VERSION 5.7 ;
BUSBITCHARS "[]" ;
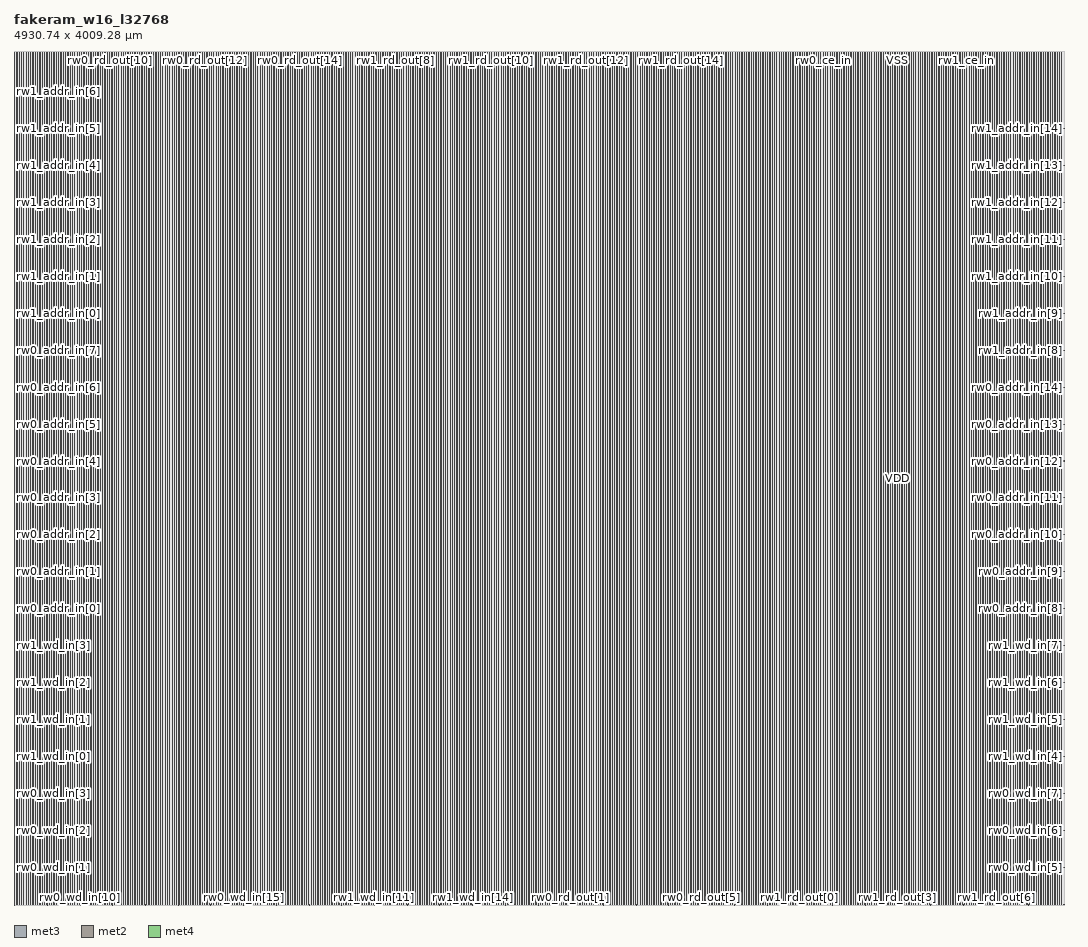
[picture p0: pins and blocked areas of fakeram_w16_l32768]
MACRO fakeram_w16_l32768
  FOREIGN fakeram_w16_l32768 0 0 ;
  SYMMETRY X Y R90 ;
  SIZE 4930.740 BY 4009.280 ;
  CLASS BLOCK ;
  PIN rw0_wd_in[0]
    DIRECTION INPUT ;
    USE SIGNAL ;
    SHAPE ABUTMENT ;
    PORT
      LAYER met3 ;
      RECT 0.000 3.930 0.900 4.230 ;
    END
  END rw0_wd_in[0]
  PIN rw0_wd_in[1]
    DIRECTION INPUT ;
    USE SIGNAL ;
    SHAPE ABUTMENT ;
    PORT
      LAYER met3 ;
      RECT 0.000 177.330 0.900 177.630 ;
    END
  END rw0_wd_in[1]
  PIN rw0_wd_in[2]
    DIRECTION INPUT ;
    USE SIGNAL ;
    SHAPE ABUTMENT ;
    PORT
      LAYER met3 ;
      RECT 0.000 350.730 0.900 351.030 ;
    END
  END rw0_wd_in[2]
  PIN rw0_wd_in[3]
    DIRECTION INPUT ;
    USE SIGNAL ;
    SHAPE ABUTMENT ;
    PORT
      LAYER met3 ;
      RECT 0.000 524.130 0.900 524.430 ;
    END
  END rw0_wd_in[3]
  PIN rw0_wd_in[4]
    DIRECTION INPUT ;
    USE SIGNAL ;
    SHAPE ABUTMENT ;
    PORT
      LAYER met3 ;
      RECT 4929.840 3.930 4930.740 4.230 ;
    END
  END rw0_wd_in[4]
  PIN rw0_wd_in[5]
    DIRECTION INPUT ;
    USE SIGNAL ;
    SHAPE ABUTMENT ;
    PORT
      LAYER met3 ;
      RECT 4929.840 177.330 4930.740 177.630 ;
    END
  END rw0_wd_in[5]
  PIN rw0_wd_in[6]
    DIRECTION INPUT ;
    USE SIGNAL ;
    SHAPE ABUTMENT ;
    PORT
      LAYER met3 ;
      RECT 4929.840 350.730 4930.740 351.030 ;
    END
  END rw0_wd_in[6]
  PIN rw0_wd_in[7]
    DIRECTION INPUT ;
    USE SIGNAL ;
    SHAPE ABUTMENT ;
    PORT
      LAYER met3 ;
      RECT 4929.840 524.130 4930.740 524.430 ;
    END
  END rw0_wd_in[7]
  PIN rw0_wd_in[8]
    DIRECTION INPUT ;
    USE SIGNAL ;
    SHAPE ABUTMENT ;
    PORT
      LAYER met2 ;
      RECT 2.690 0.000 2.830 0.420 ;
    END
  END rw0_wd_in[8]
  PIN rw0_wd_in[9]
    DIRECTION INPUT ;
    USE SIGNAL ;
    SHAPE ABUTMENT ;
    PORT
      LAYER met2 ;
      RECT 156.330 0.000 156.470 0.420 ;
    END
  END rw0_wd_in[9]
  PIN rw0_wd_in[10]
    DIRECTION INPUT ;
    USE SIGNAL ;
    SHAPE ABUTMENT ;
    PORT
      LAYER met2 ;
      RECT 309.970 0.000 310.110 0.420 ;
    END
  END rw0_wd_in[10]
  PIN rw0_wd_in[11]
    DIRECTION INPUT ;
    USE SIGNAL ;
    SHAPE ABUTMENT ;
    PORT
      LAYER met2 ;
      RECT 463.610 0.000 463.750 0.420 ;
    END
  END rw0_wd_in[11]
  PIN rw0_wd_in[12]
    DIRECTION INPUT ;
    USE SIGNAL ;
    SHAPE ABUTMENT ;
    PORT
      LAYER met2 ;
      RECT 617.250 0.000 617.390 0.420 ;
    END
  END rw0_wd_in[12]
  PIN rw0_wd_in[13]
    DIRECTION INPUT ;
    USE SIGNAL ;
    SHAPE ABUTMENT ;
    PORT
      LAYER met2 ;
      RECT 770.890 0.000 771.030 0.420 ;
    END
  END rw0_wd_in[13]
  PIN rw0_wd_in[14]
    DIRECTION INPUT ;
    USE SIGNAL ;
    SHAPE ABUTMENT ;
    PORT
      LAYER met2 ;
      RECT 924.530 0.000 924.670 0.420 ;
    END
  END rw0_wd_in[14]
  PIN rw0_wd_in[15]
    DIRECTION INPUT ;
    USE SIGNAL ;
    SHAPE ABUTMENT ;
    PORT
      LAYER met2 ;
      RECT 1078.170 0.000 1078.310 0.420 ;
    END
  END rw0_wd_in[15]
  PIN rw1_wd_in[0]
    DIRECTION INPUT ;
    USE SIGNAL ;
    SHAPE ABUTMENT ;
    PORT
      LAYER met3 ;
      RECT 0.000 697.530 0.900 697.830 ;
    END
  END rw1_wd_in[0]
  PIN rw1_wd_in[1]
    DIRECTION INPUT ;
    USE SIGNAL ;
    SHAPE ABUTMENT ;
    PORT
      LAYER met3 ;
      RECT 0.000 870.930 0.900 871.230 ;
    END
  END rw1_wd_in[1]
  PIN rw1_wd_in[2]
    DIRECTION INPUT ;
    USE SIGNAL ;
    SHAPE ABUTMENT ;
    PORT
      LAYER met3 ;
      RECT 0.000 1044.330 0.900 1044.630 ;
    END
  END rw1_wd_in[2]
  PIN rw1_wd_in[3]
    DIRECTION INPUT ;
    USE SIGNAL ;
    SHAPE ABUTMENT ;
    PORT
      LAYER met3 ;
      RECT 0.000 1217.730 0.900 1218.030 ;
    END
  END rw1_wd_in[3]
  PIN rw1_wd_in[4]
    DIRECTION INPUT ;
    USE SIGNAL ;
    SHAPE ABUTMENT ;
    PORT
      LAYER met3 ;
      RECT 4929.840 697.530 4930.740 697.830 ;
    END
  END rw1_wd_in[4]
  PIN rw1_wd_in[5]
    DIRECTION INPUT ;
    USE SIGNAL ;
    SHAPE ABUTMENT ;
    PORT
      LAYER met3 ;
      RECT 4929.840 870.930 4930.740 871.230 ;
    END
  END rw1_wd_in[5]
  PIN rw1_wd_in[6]
    DIRECTION INPUT ;
    USE SIGNAL ;
    SHAPE ABUTMENT ;
    PORT
      LAYER met3 ;
      RECT 4929.840 1044.330 4930.740 1044.630 ;
    END
  END rw1_wd_in[6]
  PIN rw1_wd_in[7]
    DIRECTION INPUT ;
    USE SIGNAL ;
    SHAPE ABUTMENT ;
    PORT
      LAYER met3 ;
      RECT 4929.840 1217.730 4930.740 1218.030 ;
    END
  END rw1_wd_in[7]
  PIN rw1_wd_in[8]
    DIRECTION INPUT ;
    USE SIGNAL ;
    SHAPE ABUTMENT ;
    PORT
      LAYER met2 ;
      RECT 1231.810 0.000 1231.950 0.420 ;
    END
  END rw1_wd_in[8]
  PIN rw1_wd_in[9]
    DIRECTION INPUT ;
    USE SIGNAL ;
    SHAPE ABUTMENT ;
    PORT
      LAYER met2 ;
      RECT 1385.450 0.000 1385.590 0.420 ;
    END
  END rw1_wd_in[9]
  PIN rw1_wd_in[10]
    DIRECTION INPUT ;
    USE SIGNAL ;
    SHAPE ABUTMENT ;
    PORT
      LAYER met2 ;
      RECT 1539.090 0.000 1539.230 0.420 ;
    END
  END rw1_wd_in[10]
  PIN rw1_wd_in[11]
    DIRECTION INPUT ;
    USE SIGNAL ;
    SHAPE ABUTMENT ;
    PORT
      LAYER met2 ;
      RECT 1692.730 0.000 1692.870 0.420 ;
    END
  END rw1_wd_in[11]
  PIN rw1_wd_in[12]
    DIRECTION INPUT ;
    USE SIGNAL ;
    SHAPE ABUTMENT ;
    PORT
      LAYER met2 ;
      RECT 1846.370 0.000 1846.510 0.420 ;
    END
  END rw1_wd_in[12]
  PIN rw1_wd_in[13]
    DIRECTION INPUT ;
    USE SIGNAL ;
    SHAPE ABUTMENT ;
    PORT
      LAYER met2 ;
      RECT 2000.010 0.000 2000.150 0.420 ;
    END
  END rw1_wd_in[13]
  PIN rw1_wd_in[14]
    DIRECTION INPUT ;
    USE SIGNAL ;
    SHAPE ABUTMENT ;
    PORT
      LAYER met2 ;
      RECT 2153.650 0.000 2153.790 0.420 ;
    END
  END rw1_wd_in[14]
  PIN rw1_wd_in[15]
    DIRECTION INPUT ;
    USE SIGNAL ;
    SHAPE ABUTMENT ;
    PORT
      LAYER met2 ;
      RECT 2307.290 0.000 2307.430 0.420 ;
    END
  END rw1_wd_in[15]
  PIN rw0_rd_out[0]
    DIRECTION OUTPUT ;
    USE SIGNAL ;
    SHAPE ABUTMENT ;
    PORT
      LAYER met2 ;
      RECT 2460.930 0.000 2461.070 0.420 ;
    END
  END rw0_rd_out[0]
  PIN rw0_rd_out[1]
    DIRECTION OUTPUT ;
    USE SIGNAL ;
    SHAPE ABUTMENT ;
    PORT
      LAYER met2 ;
      RECT 2614.570 0.000 2614.710 0.420 ;
    END
  END rw0_rd_out[1]
  PIN rw0_rd_out[2]
    DIRECTION OUTPUT ;
    USE SIGNAL ;
    SHAPE ABUTMENT ;
    PORT
      LAYER met2 ;
      RECT 2768.210 0.000 2768.350 0.420 ;
    END
  END rw0_rd_out[2]
  PIN rw0_rd_out[3]
    DIRECTION OUTPUT ;
    USE SIGNAL ;
    SHAPE ABUTMENT ;
    PORT
      LAYER met2 ;
      RECT 2921.850 0.000 2921.990 0.420 ;
    END
  END rw0_rd_out[3]
  PIN rw0_rd_out[4]
    DIRECTION OUTPUT ;
    USE SIGNAL ;
    SHAPE ABUTMENT ;
    PORT
      LAYER met2 ;
      RECT 3075.490 0.000 3075.630 0.420 ;
    END
  END rw0_rd_out[4]
  PIN rw0_rd_out[5]
    DIRECTION OUTPUT ;
    USE SIGNAL ;
    SHAPE ABUTMENT ;
    PORT
      LAYER met2 ;
      RECT 3229.130 0.000 3229.270 0.420 ;
    END
  END rw0_rd_out[5]
  PIN rw0_rd_out[6]
    DIRECTION OUTPUT ;
    USE SIGNAL ;
    SHAPE ABUTMENT ;
    PORT
      LAYER met2 ;
      RECT 3382.770 0.000 3382.910 0.420 ;
    END
  END rw0_rd_out[6]
  PIN rw0_rd_out[7]
    DIRECTION OUTPUT ;
    USE SIGNAL ;
    SHAPE ABUTMENT ;
    PORT
      LAYER met2 ;
      RECT 3536.410 0.000 3536.550 0.420 ;
    END
  END rw0_rd_out[7]
  PIN rw0_rd_out[8]
    DIRECTION OUTPUT ;
    USE SIGNAL ;
    SHAPE ABUTMENT ;
    PORT
      LAYER met2 ;
      RECT 2.690 4008.860 2.830 4009.280 ;
    END
  END rw0_rd_out[8]
  PIN rw0_rd_out[9]
    DIRECTION OUTPUT ;
    USE SIGNAL ;
    SHAPE ABUTMENT ;
    PORT
      LAYER met2 ;
      RECT 226.250 4008.860 226.390 4009.280 ;
    END
  END rw0_rd_out[9]
  PIN rw0_rd_out[10]
    DIRECTION OUTPUT ;
    USE SIGNAL ;
    SHAPE ABUTMENT ;
    PORT
      LAYER met2 ;
      RECT 449.810 4008.860 449.950 4009.280 ;
    END
  END rw0_rd_out[10]
  PIN rw0_rd_out[11]
    DIRECTION OUTPUT ;
    USE SIGNAL ;
    SHAPE ABUTMENT ;
    PORT
      LAYER met2 ;
      RECT 673.370 4008.860 673.510 4009.280 ;
    END
  END rw0_rd_out[11]
  PIN rw0_rd_out[12]
    DIRECTION OUTPUT ;
    USE SIGNAL ;
    SHAPE ABUTMENT ;
    PORT
      LAYER met2 ;
      RECT 896.930 4008.860 897.070 4009.280 ;
    END
  END rw0_rd_out[12]
  PIN rw0_rd_out[13]
    DIRECTION OUTPUT ;
    USE SIGNAL ;
    SHAPE ABUTMENT ;
    PORT
      LAYER met2 ;
      RECT 1120.490 4008.860 1120.630 4009.280 ;
    END
  END rw0_rd_out[13]
  PIN rw0_rd_out[14]
    DIRECTION OUTPUT ;
    USE SIGNAL ;
    SHAPE ABUTMENT ;
    PORT
      LAYER met2 ;
      RECT 1344.050 4008.860 1344.190 4009.280 ;
    END
  END rw0_rd_out[14]
  PIN rw0_rd_out[15]
    DIRECTION OUTPUT ;
    USE SIGNAL ;
    SHAPE ABUTMENT ;
    PORT
      LAYER met2 ;
      RECT 1567.610 4008.860 1567.750 4009.280 ;
    END
  END rw0_rd_out[15]
  PIN rw1_rd_out[0]
    DIRECTION OUTPUT ;
    USE SIGNAL ;
    SHAPE ABUTMENT ;
    PORT
      LAYER met2 ;
      RECT 3690.050 0.000 3690.190 0.420 ;
    END
  END rw1_rd_out[0]
  PIN rw1_rd_out[1]
    DIRECTION OUTPUT ;
    USE SIGNAL ;
    SHAPE ABUTMENT ;
    PORT
      LAYER met2 ;
      RECT 3843.690 0.000 3843.830 0.420 ;
    END
  END rw1_rd_out[1]
  PIN rw1_rd_out[2]
    DIRECTION OUTPUT ;
    USE SIGNAL ;
    SHAPE ABUTMENT ;
    PORT
      LAYER met2 ;
      RECT 3997.330 0.000 3997.470 0.420 ;
    END
  END rw1_rd_out[2]
  PIN rw1_rd_out[3]
    DIRECTION OUTPUT ;
    USE SIGNAL ;
    SHAPE ABUTMENT ;
    PORT
      LAYER met2 ;
      RECT 4150.970 0.000 4151.110 0.420 ;
    END
  END rw1_rd_out[3]
  PIN rw1_rd_out[4]
    DIRECTION OUTPUT ;
    USE SIGNAL ;
    SHAPE ABUTMENT ;
    PORT
      LAYER met2 ;
      RECT 4304.610 0.000 4304.750 0.420 ;
    END
  END rw1_rd_out[4]
  PIN rw1_rd_out[5]
    DIRECTION OUTPUT ;
    USE SIGNAL ;
    SHAPE ABUTMENT ;
    PORT
      LAYER met2 ;
      RECT 4458.250 0.000 4458.390 0.420 ;
    END
  END rw1_rd_out[5]
  PIN rw1_rd_out[6]
    DIRECTION OUTPUT ;
    USE SIGNAL ;
    SHAPE ABUTMENT ;
    PORT
      LAYER met2 ;
      RECT 4611.890 0.000 4612.030 0.420 ;
    END
  END rw1_rd_out[6]
  PIN rw1_rd_out[7]
    DIRECTION OUTPUT ;
    USE SIGNAL ;
    SHAPE ABUTMENT ;
    PORT
      LAYER met2 ;
      RECT 4765.530 0.000 4765.670 0.420 ;
    END
  END rw1_rd_out[7]
  PIN rw1_rd_out[8]
    DIRECTION OUTPUT ;
    USE SIGNAL ;
    SHAPE ABUTMENT ;
    PORT
      LAYER met2 ;
      RECT 1791.170 4008.860 1791.310 4009.280 ;
    END
  END rw1_rd_out[8]
  PIN rw1_rd_out[9]
    DIRECTION OUTPUT ;
    USE SIGNAL ;
    SHAPE ABUTMENT ;
    PORT
      LAYER met2 ;
      RECT 2014.730 4008.860 2014.870 4009.280 ;
    END
  END rw1_rd_out[9]
  PIN rw1_rd_out[10]
    DIRECTION OUTPUT ;
    USE SIGNAL ;
    SHAPE ABUTMENT ;
    PORT
      LAYER met2 ;
      RECT 2238.290 4008.860 2238.430 4009.280 ;
    END
  END rw1_rd_out[10]
  PIN rw1_rd_out[11]
    DIRECTION OUTPUT ;
    USE SIGNAL ;
    SHAPE ABUTMENT ;
    PORT
      LAYER met2 ;
      RECT 2461.850 4008.860 2461.990 4009.280 ;
    END
  END rw1_rd_out[11]
  PIN rw1_rd_out[12]
    DIRECTION OUTPUT ;
    USE SIGNAL ;
    SHAPE ABUTMENT ;
    PORT
      LAYER met2 ;
      RECT 2685.410 4008.860 2685.550 4009.280 ;
    END
  END rw1_rd_out[12]
  PIN rw1_rd_out[13]
    DIRECTION OUTPUT ;
    USE SIGNAL ;
    SHAPE ABUTMENT ;
    PORT
      LAYER met2 ;
      RECT 2908.970 4008.860 2909.110 4009.280 ;
    END
  END rw1_rd_out[13]
  PIN rw1_rd_out[14]
    DIRECTION OUTPUT ;
    USE SIGNAL ;
    SHAPE ABUTMENT ;
    PORT
      LAYER met2 ;
      RECT 3132.530 4008.860 3132.670 4009.280 ;
    END
  END rw1_rd_out[14]
  PIN rw1_rd_out[15]
    DIRECTION OUTPUT ;
    USE SIGNAL ;
    SHAPE ABUTMENT ;
    PORT
      LAYER met2 ;
      RECT 3356.090 4008.860 3356.230 4009.280 ;
    END
  END rw1_rd_out[15]
  PIN rw0_addr_in[0]
    DIRECTION INPUT ;
    USE SIGNAL ;
    SHAPE ABUTMENT ;
    PORT
      LAYER met3 ;
      RECT 0.000 1391.130 0.900 1391.430 ;
    END
  END rw0_addr_in[0]
  PIN rw0_addr_in[1]
    DIRECTION INPUT ;
    USE SIGNAL ;
    SHAPE ABUTMENT ;
    PORT
      LAYER met3 ;
      RECT 0.000 1564.530 0.900 1564.830 ;
    END
  END rw0_addr_in[1]
  PIN rw0_addr_in[2]
    DIRECTION INPUT ;
    USE SIGNAL ;
    SHAPE ABUTMENT ;
    PORT
      LAYER met3 ;
      RECT 0.000 1737.930 0.900 1738.230 ;
    END
  END rw0_addr_in[2]
  PIN rw0_addr_in[3]
    DIRECTION INPUT ;
    USE SIGNAL ;
    SHAPE ABUTMENT ;
    PORT
      LAYER met3 ;
      RECT 0.000 1911.330 0.900 1911.630 ;
    END
  END rw0_addr_in[3]
  PIN rw0_addr_in[4]
    DIRECTION INPUT ;
    USE SIGNAL ;
    SHAPE ABUTMENT ;
    PORT
      LAYER met3 ;
      RECT 0.000 2084.730 0.900 2085.030 ;
    END
  END rw0_addr_in[4]
  PIN rw0_addr_in[5]
    DIRECTION INPUT ;
    USE SIGNAL ;
    SHAPE ABUTMENT ;
    PORT
      LAYER met3 ;
      RECT 0.000 2258.130 0.900 2258.430 ;
    END
  END rw0_addr_in[5]
  PIN rw0_addr_in[6]
    DIRECTION INPUT ;
    USE SIGNAL ;
    SHAPE ABUTMENT ;
    PORT
      LAYER met3 ;
      RECT 0.000 2431.530 0.900 2431.830 ;
    END
  END rw0_addr_in[6]
  PIN rw0_addr_in[7]
    DIRECTION INPUT ;
    USE SIGNAL ;
    SHAPE ABUTMENT ;
    PORT
      LAYER met3 ;
      RECT 0.000 2604.930 0.900 2605.230 ;
    END
  END rw0_addr_in[7]
  PIN rw0_addr_in[8]
    DIRECTION INPUT ;
    USE SIGNAL ;
    SHAPE ABUTMENT ;
    PORT
      LAYER met3 ;
      RECT 4929.840 1391.130 4930.740 1391.430 ;
    END
  END rw0_addr_in[8]
  PIN rw0_addr_in[9]
    DIRECTION INPUT ;
    USE SIGNAL ;
    SHAPE ABUTMENT ;
    PORT
      LAYER met3 ;
      RECT 4929.840 1564.530 4930.740 1564.830 ;
    END
  END rw0_addr_in[9]
  PIN rw0_addr_in[10]
    DIRECTION INPUT ;
    USE SIGNAL ;
    SHAPE ABUTMENT ;
    PORT
      LAYER met3 ;
      RECT 4929.840 1737.930 4930.740 1738.230 ;
    END
  END rw0_addr_in[10]
  PIN rw0_addr_in[11]
    DIRECTION INPUT ;
    USE SIGNAL ;
    SHAPE ABUTMENT ;
    PORT
      LAYER met3 ;
      RECT 4929.840 1911.330 4930.740 1911.630 ;
    END
  END rw0_addr_in[11]
  PIN rw0_addr_in[12]
    DIRECTION INPUT ;
    USE SIGNAL ;
    SHAPE ABUTMENT ;
    PORT
      LAYER met3 ;
      RECT 4929.840 2084.730 4930.740 2085.030 ;
    END
  END rw0_addr_in[12]
  PIN rw0_addr_in[13]
    DIRECTION INPUT ;
    USE SIGNAL ;
    SHAPE ABUTMENT ;
    PORT
      LAYER met3 ;
      RECT 4929.840 2258.130 4930.740 2258.430 ;
    END
  END rw0_addr_in[13]
  PIN rw0_addr_in[14]
    DIRECTION INPUT ;
    USE SIGNAL ;
    SHAPE ABUTMENT ;
    PORT
      LAYER met3 ;
      RECT 4929.840 2431.530 4930.740 2431.830 ;
    END
  END rw0_addr_in[14]
  PIN rw1_addr_in[0]
    DIRECTION INPUT ;
    USE SIGNAL ;
    SHAPE ABUTMENT ;
    PORT
      LAYER met3 ;
      RECT 0.000 2778.330 0.900 2778.630 ;
    END
  END rw1_addr_in[0]
  PIN rw1_addr_in[1]
    DIRECTION INPUT ;
    USE SIGNAL ;
    SHAPE ABUTMENT ;
    PORT
      LAYER met3 ;
      RECT 0.000 2951.730 0.900 2952.030 ;
    END
  END rw1_addr_in[1]
  PIN rw1_addr_in[2]
    DIRECTION INPUT ;
    USE SIGNAL ;
    SHAPE ABUTMENT ;
    PORT
      LAYER met3 ;
      RECT 0.000 3125.130 0.900 3125.430 ;
    END
  END rw1_addr_in[2]
  PIN rw1_addr_in[3]
    DIRECTION INPUT ;
    USE SIGNAL ;
    SHAPE ABUTMENT ;
    PORT
      LAYER met3 ;
      RECT 0.000 3298.530 0.900 3298.830 ;
    END
  END rw1_addr_in[3]
  PIN rw1_addr_in[4]
    DIRECTION INPUT ;
    USE SIGNAL ;
    SHAPE ABUTMENT ;
    PORT
      LAYER met3 ;
      RECT 0.000 3471.930 0.900 3472.230 ;
    END
  END rw1_addr_in[4]
  PIN rw1_addr_in[5]
    DIRECTION INPUT ;
    USE SIGNAL ;
    SHAPE ABUTMENT ;
    PORT
      LAYER met3 ;
      RECT 0.000 3645.330 0.900 3645.630 ;
    END
  END rw1_addr_in[5]
  PIN rw1_addr_in[6]
    DIRECTION INPUT ;
    USE SIGNAL ;
    SHAPE ABUTMENT ;
    PORT
      LAYER met3 ;
      RECT 0.000 3818.730 0.900 3819.030 ;
    END
  END rw1_addr_in[6]
  PIN rw1_addr_in[7]
    DIRECTION INPUT ;
    USE SIGNAL ;
    SHAPE ABUTMENT ;
    PORT
      LAYER met3 ;
      RECT 0.000 3992.130 0.900 3992.430 ;
    END
  END rw1_addr_in[7]
  PIN rw1_addr_in[8]
    DIRECTION INPUT ;
    USE SIGNAL ;
    SHAPE ABUTMENT ;
    PORT
      LAYER met3 ;
      RECT 4929.840 2604.930 4930.740 2605.230 ;
    END
  END rw1_addr_in[8]
  PIN rw1_addr_in[9]
    DIRECTION INPUT ;
    USE SIGNAL ;
    SHAPE ABUTMENT ;
    PORT
      LAYER met3 ;
      RECT 4929.840 2778.330 4930.740 2778.630 ;
    END
  END rw1_addr_in[9]
  PIN rw1_addr_in[10]
    DIRECTION INPUT ;
    USE SIGNAL ;
    SHAPE ABUTMENT ;
    PORT
      LAYER met3 ;
      RECT 4929.840 2951.730 4930.740 2952.030 ;
    END
  END rw1_addr_in[10]
  PIN rw1_addr_in[11]
    DIRECTION INPUT ;
    USE SIGNAL ;
    SHAPE ABUTMENT ;
    PORT
      LAYER met3 ;
      RECT 4929.840 3125.130 4930.740 3125.430 ;
    END
  END rw1_addr_in[11]
  PIN rw1_addr_in[12]
    DIRECTION INPUT ;
    USE SIGNAL ;
    SHAPE ABUTMENT ;
    PORT
      LAYER met3 ;
      RECT 4929.840 3298.530 4930.740 3298.830 ;
    END
  END rw1_addr_in[12]
  PIN rw1_addr_in[13]
    DIRECTION INPUT ;
    USE SIGNAL ;
    SHAPE ABUTMENT ;
    PORT
      LAYER met3 ;
      RECT 4929.840 3471.930 4930.740 3472.230 ;
    END
  END rw1_addr_in[13]
  PIN rw1_addr_in[14]
    DIRECTION INPUT ;
    USE SIGNAL ;
    SHAPE ABUTMENT ;
    PORT
      LAYER met3 ;
      RECT 4929.840 3645.330 4930.740 3645.630 ;
    END
  END rw1_addr_in[14]
  PIN rw0_we_in
    DIRECTION INPUT ;
    USE SIGNAL ;
    SHAPE ABUTMENT ;
    PORT
      LAYER met2 ;
      RECT 3579.650 4008.860 3579.790 4009.280 ;
    END
  END rw0_we_in
  PIN rw0_ce_in
    DIRECTION INPUT ;
    USE SIGNAL ;
    SHAPE ABUTMENT ;
    PORT
      LAYER met2 ;
      RECT 3803.210 4008.860 3803.350 4009.280 ;
    END
  END rw0_ce_in
  PIN rw0_clk
    DIRECTION INPUT ;
    USE SIGNAL ;
    SHAPE ABUTMENT ;
    PORT
      LAYER met2 ;
      RECT 4026.770 4008.860 4026.910 4009.280 ;
    END
  END rw0_clk
  PIN rw1_we_in
    DIRECTION INPUT ;
    USE SIGNAL ;
    SHAPE ABUTMENT ;
    PORT
      LAYER met2 ;
      RECT 4250.330 4008.860 4250.470 4009.280 ;
    END
  END rw1_we_in
  PIN rw1_ce_in
    DIRECTION INPUT ;
    USE SIGNAL ;
    SHAPE ABUTMENT ;
    PORT
      LAYER met2 ;
      RECT 4473.890 4008.860 4474.030 4009.280 ;
    END
  END rw1_ce_in
  PIN rw1_clk
    DIRECTION INPUT ;
    USE SIGNAL ;
    SHAPE ABUTMENT ;
    PORT
      LAYER met2 ;
      RECT 4697.450 4008.860 4697.590 4009.280 ;
    END
  END rw1_clk
  PIN VSS
    DIRECTION INOUT ;
    USE GROUND ;
    PORT
      LAYER met4 ;
      RECT 2.160 4.080 3.360 4005.200 ;
      RECT 13.040 4.080 14.240 4005.200 ;
      RECT 23.920 4.080 25.120 4005.200 ;
      RECT 34.800 4.080 36.000 4005.200 ;
      RECT 45.680 4.080 46.880 4005.200 ;
      RECT 56.560 4.080 57.760 4005.200 ;
      RECT 67.440 4.080 68.640 4005.200 ;
      RECT 78.320 4.080 79.520 4005.200 ;
      RECT 89.200 4.080 90.400 4005.200 ;
      RECT 100.080 4.080 101.280 4005.200 ;
      RECT 110.960 4.080 112.160 4005.200 ;
      RECT 121.840 4.080 123.040 4005.200 ;
      RECT 132.720 4.080 133.920 4005.200 ;
      RECT 143.600 4.080 144.800 4005.200 ;
      RECT 154.480 4.080 155.680 4005.200 ;
      RECT 165.360 4.080 166.560 4005.200 ;
      RECT 176.240 4.080 177.440 4005.200 ;
      RECT 187.120 4.080 188.320 4005.200 ;
      RECT 198.000 4.080 199.200 4005.200 ;
      RECT 208.880 4.080 210.080 4005.200 ;
      RECT 219.760 4.080 220.960 4005.200 ;
      RECT 230.640 4.080 231.840 4005.200 ;
      RECT 241.520 4.080 242.720 4005.200 ;
      RECT 252.400 4.080 253.600 4005.200 ;
      RECT 263.280 4.080 264.480 4005.200 ;
      RECT 274.160 4.080 275.360 4005.200 ;
      RECT 285.040 4.080 286.240 4005.200 ;
      RECT 295.920 4.080 297.120 4005.200 ;
      RECT 306.800 4.080 308.000 4005.200 ;
      RECT 317.680 4.080 318.880 4005.200 ;
      RECT 328.560 4.080 329.760 4005.200 ;
      RECT 339.440 4.080 340.640 4005.200 ;
      RECT 350.320 4.080 351.520 4005.200 ;
      RECT 361.200 4.080 362.400 4005.200 ;
      RECT 372.080 4.080 373.280 4005.200 ;
      RECT 382.960 4.080 384.160 4005.200 ;
      RECT 393.840 4.080 395.040 4005.200 ;
      RECT 404.720 4.080 405.920 4005.200 ;
      RECT 415.600 4.080 416.800 4005.200 ;
      RECT 426.480 4.080 427.680 4005.200 ;
      RECT 437.360 4.080 438.560 4005.200 ;
      RECT 448.240 4.080 449.440 4005.200 ;
      RECT 459.120 4.080 460.320 4005.200 ;
      RECT 470.000 4.080 471.200 4005.200 ;
      RECT 480.880 4.080 482.080 4005.200 ;
      RECT 491.760 4.080 492.960 4005.200 ;
      RECT 502.640 4.080 503.840 4005.200 ;
      RECT 513.520 4.080 514.720 4005.200 ;
      RECT 524.400 4.080 525.600 4005.200 ;
      RECT 535.280 4.080 536.480 4005.200 ;
      RECT 546.160 4.080 547.360 4005.200 ;
      RECT 557.040 4.080 558.240 4005.200 ;
      RECT 567.920 4.080 569.120 4005.200 ;
      RECT 578.800 4.080 580.000 4005.200 ;
      RECT 589.680 4.080 590.880 4005.200 ;
      RECT 600.560 4.080 601.760 4005.200 ;
      RECT 611.440 4.080 612.640 4005.200 ;
      RECT 622.320 4.080 623.520 4005.200 ;
      RECT 633.200 4.080 634.400 4005.200 ;
      RECT 644.080 4.080 645.280 4005.200 ;
      RECT 654.960 4.080 656.160 4005.200 ;
      RECT 665.840 4.080 667.040 4005.200 ;
      RECT 676.720 4.080 677.920 4005.200 ;
      RECT 687.600 4.080 688.800 4005.200 ;
      RECT 698.480 4.080 699.680 4005.200 ;
      RECT 709.360 4.080 710.560 4005.200 ;
      RECT 720.240 4.080 721.440 4005.200 ;
      RECT 731.120 4.080 732.320 4005.200 ;
      RECT 742.000 4.080 743.200 4005.200 ;
      RECT 752.880 4.080 754.080 4005.200 ;
      RECT 763.760 4.080 764.960 4005.200 ;
      RECT 774.640 4.080 775.840 4005.200 ;
      RECT 785.520 4.080 786.720 4005.200 ;
      RECT 796.400 4.080 797.600 4005.200 ;
      RECT 807.280 4.080 808.480 4005.200 ;
      RECT 818.160 4.080 819.360 4005.200 ;
      RECT 829.040 4.080 830.240 4005.200 ;
      RECT 839.920 4.080 841.120 4005.200 ;
      RECT 850.800 4.080 852.000 4005.200 ;
      RECT 861.680 4.080 862.880 4005.200 ;
      RECT 872.560 4.080 873.760 4005.200 ;
      RECT 883.440 4.080 884.640 4005.200 ;
      RECT 894.320 4.080 895.520 4005.200 ;
      RECT 905.200 4.080 906.400 4005.200 ;
      RECT 916.080 4.080 917.280 4005.200 ;
      RECT 926.960 4.080 928.160 4005.200 ;
      RECT 937.840 4.080 939.040 4005.200 ;
      RECT 948.720 4.080 949.920 4005.200 ;
      RECT 959.600 4.080 960.800 4005.200 ;
      RECT 970.480 4.080 971.680 4005.200 ;
      RECT 981.360 4.080 982.560 4005.200 ;
      RECT 992.240 4.080 993.440 4005.200 ;
      RECT 1003.120 4.080 1004.320 4005.200 ;
      RECT 1014.000 4.080 1015.200 4005.200 ;
      RECT 1024.880 4.080 1026.080 4005.200 ;
      RECT 1035.760 4.080 1036.960 4005.200 ;
      RECT 1046.640 4.080 1047.840 4005.200 ;
      RECT 1057.520 4.080 1058.720 4005.200 ;
      RECT 1068.400 4.080 1069.600 4005.200 ;
      RECT 1079.280 4.080 1080.480 4005.200 ;
      RECT 1090.160 4.080 1091.360 4005.200 ;
      RECT 1101.040 4.080 1102.240 4005.200 ;
      RECT 1111.920 4.080 1113.120 4005.200 ;
      RECT 1122.800 4.080 1124.000 4005.200 ;
      RECT 1133.680 4.080 1134.880 4005.200 ;
      RECT 1144.560 4.080 1145.760 4005.200 ;
      RECT 1155.440 4.080 1156.640 4005.200 ;
      RECT 1166.320 4.080 1167.520 4005.200 ;
      RECT 1177.200 4.080 1178.400 4005.200 ;
      RECT 1188.080 4.080 1189.280 4005.200 ;
      RECT 1198.960 4.080 1200.160 4005.200 ;
      RECT 1209.840 4.080 1211.040 4005.200 ;
      RECT 1220.720 4.080 1221.920 4005.200 ;
      RECT 1231.600 4.080 1232.800 4005.200 ;
      RECT 1242.480 4.080 1243.680 4005.200 ;
      RECT 1253.360 4.080 1254.560 4005.200 ;
      RECT 1264.240 4.080 1265.440 4005.200 ;
      RECT 1275.120 4.080 1276.320 4005.200 ;
      RECT 1286.000 4.080 1287.200 4005.200 ;
      RECT 1296.880 4.080 1298.080 4005.200 ;
      RECT 1307.760 4.080 1308.960 4005.200 ;
      RECT 1318.640 4.080 1319.840 4005.200 ;
      RECT 1329.520 4.080 1330.720 4005.200 ;
      RECT 1340.400 4.080 1341.600 4005.200 ;
      RECT 1351.280 4.080 1352.480 4005.200 ;
      RECT 1362.160 4.080 1363.360 4005.200 ;
      RECT 1373.040 4.080 1374.240 4005.200 ;
      RECT 1383.920 4.080 1385.120 4005.200 ;
      RECT 1394.800 4.080 1396.000 4005.200 ;
      RECT 1405.680 4.080 1406.880 4005.200 ;
      RECT 1416.560 4.080 1417.760 4005.200 ;
      RECT 1427.440 4.080 1428.640 4005.200 ;
      RECT 1438.320 4.080 1439.520 4005.200 ;
      RECT 1449.200 4.080 1450.400 4005.200 ;
      RECT 1460.080 4.080 1461.280 4005.200 ;
      RECT 1470.960 4.080 1472.160 4005.200 ;
      RECT 1481.840 4.080 1483.040 4005.200 ;
      RECT 1492.720 4.080 1493.920 4005.200 ;
      RECT 1503.600 4.080 1504.800 4005.200 ;
      RECT 1514.480 4.080 1515.680 4005.200 ;
      RECT 1525.360 4.080 1526.560 4005.200 ;
      RECT 1536.240 4.080 1537.440 4005.200 ;
      RECT 1547.120 4.080 1548.320 4005.200 ;
      RECT 1558.000 4.080 1559.200 4005.200 ;
      RECT 1568.880 4.080 1570.080 4005.200 ;
      RECT 1579.760 4.080 1580.960 4005.200 ;
      RECT 1590.640 4.080 1591.840 4005.200 ;
      RECT 1601.520 4.080 1602.720 4005.200 ;
      RECT 1612.400 4.080 1613.600 4005.200 ;
      RECT 1623.280 4.080 1624.480 4005.200 ;
      RECT 1634.160 4.080 1635.360 4005.200 ;
      RECT 1645.040 4.080 1646.240 4005.200 ;
      RECT 1655.920 4.080 1657.120 4005.200 ;
      RECT 1666.800 4.080 1668.000 4005.200 ;
      RECT 1677.680 4.080 1678.880 4005.200 ;
      RECT 1688.560 4.080 1689.760 4005.200 ;
      RECT 1699.440 4.080 1700.640 4005.200 ;
      RECT 1710.320 4.080 1711.520 4005.200 ;
      RECT 1721.200 4.080 1722.400 4005.200 ;
      RECT 1732.080 4.080 1733.280 4005.200 ;
      RECT 1742.960 4.080 1744.160 4005.200 ;
      RECT 1753.840 4.080 1755.040 4005.200 ;
      RECT 1764.720 4.080 1765.920 4005.200 ;
      RECT 1775.600 4.080 1776.800 4005.200 ;
      RECT 1786.480 4.080 1787.680 4005.200 ;
      RECT 1797.360 4.080 1798.560 4005.200 ;
      RECT 1808.240 4.080 1809.440 4005.200 ;
      RECT 1819.120 4.080 1820.320 4005.200 ;
      RECT 1830.000 4.080 1831.200 4005.200 ;
      RECT 1840.880 4.080 1842.080 4005.200 ;
      RECT 1851.760 4.080 1852.960 4005.200 ;
      RECT 1862.640 4.080 1863.840 4005.200 ;
      RECT 1873.520 4.080 1874.720 4005.200 ;
      RECT 1884.400 4.080 1885.600 4005.200 ;
      RECT 1895.280 4.080 1896.480 4005.200 ;
      RECT 1906.160 4.080 1907.360 4005.200 ;
      RECT 1917.040 4.080 1918.240 4005.200 ;
      RECT 1927.920 4.080 1929.120 4005.200 ;
      RECT 1938.800 4.080 1940.000 4005.200 ;
      RECT 1949.680 4.080 1950.880 4005.200 ;
      RECT 1960.560 4.080 1961.760 4005.200 ;
      RECT 1971.440 4.080 1972.640 4005.200 ;
      RECT 1982.320 4.080 1983.520 4005.200 ;
      RECT 1993.200 4.080 1994.400 4005.200 ;
      RECT 2004.080 4.080 2005.280 4005.200 ;
      RECT 2014.960 4.080 2016.160 4005.200 ;
      RECT 2025.840 4.080 2027.040 4005.200 ;
      RECT 2036.720 4.080 2037.920 4005.200 ;
      RECT 2047.600 4.080 2048.800 4005.200 ;
      RECT 2058.480 4.080 2059.680 4005.200 ;
      RECT 2069.360 4.080 2070.560 4005.200 ;
      RECT 2080.240 4.080 2081.440 4005.200 ;
      RECT 2091.120 4.080 2092.320 4005.200 ;
      RECT 2102.000 4.080 2103.200 4005.200 ;
      RECT 2112.880 4.080 2114.080 4005.200 ;
      RECT 2123.760 4.080 2124.960 4005.200 ;
      RECT 2134.640 4.080 2135.840 4005.200 ;
      RECT 2145.520 4.080 2146.720 4005.200 ;
      RECT 2156.400 4.080 2157.600 4005.200 ;
      RECT 2167.280 4.080 2168.480 4005.200 ;
      RECT 2178.160 4.080 2179.360 4005.200 ;
      RECT 2189.040 4.080 2190.240 4005.200 ;
      RECT 2199.920 4.080 2201.120 4005.200 ;
      RECT 2210.800 4.080 2212.000 4005.200 ;
      RECT 2221.680 4.080 2222.880 4005.200 ;
      RECT 2232.560 4.080 2233.760 4005.200 ;
      RECT 2243.440 4.080 2244.640 4005.200 ;
      RECT 2254.320 4.080 2255.520 4005.200 ;
      RECT 2265.200 4.080 2266.400 4005.200 ;
      RECT 2276.080 4.080 2277.280 4005.200 ;
      RECT 2286.960 4.080 2288.160 4005.200 ;
      RECT 2297.840 4.080 2299.040 4005.200 ;
      RECT 2308.720 4.080 2309.920 4005.200 ;
      RECT 2319.600 4.080 2320.800 4005.200 ;
      RECT 2330.480 4.080 2331.680 4005.200 ;
      RECT 2341.360 4.080 2342.560 4005.200 ;
      RECT 2352.240 4.080 2353.440 4005.200 ;
      RECT 2363.120 4.080 2364.320 4005.200 ;
      RECT 2374.000 4.080 2375.200 4005.200 ;
      RECT 2384.880 4.080 2386.080 4005.200 ;
      RECT 2395.760 4.080 2396.960 4005.200 ;
      RECT 2406.640 4.080 2407.840 4005.200 ;
      RECT 2417.520 4.080 2418.720 4005.200 ;
      RECT 2428.400 4.080 2429.600 4005.200 ;
      RECT 2439.280 4.080 2440.480 4005.200 ;
      RECT 2450.160 4.080 2451.360 4005.200 ;
      RECT 2461.040 4.080 2462.240 4005.200 ;
      RECT 2471.920 4.080 2473.120 4005.200 ;
      RECT 2482.800 4.080 2484.000 4005.200 ;
      RECT 2493.680 4.080 2494.880 4005.200 ;
      RECT 2504.560 4.080 2505.760 4005.200 ;
      RECT 2515.440 4.080 2516.640 4005.200 ;
      RECT 2526.320 4.080 2527.520 4005.200 ;
      RECT 2537.200 4.080 2538.400 4005.200 ;
      RECT 2548.080 4.080 2549.280 4005.200 ;
      RECT 2558.960 4.080 2560.160 4005.200 ;
      RECT 2569.840 4.080 2571.040 4005.200 ;
      RECT 2580.720 4.080 2581.920 4005.200 ;
      RECT 2591.600 4.080 2592.800 4005.200 ;
      RECT 2602.480 4.080 2603.680 4005.200 ;
      RECT 2613.360 4.080 2614.560 4005.200 ;
      RECT 2624.240 4.080 2625.440 4005.200 ;
      RECT 2635.120 4.080 2636.320 4005.200 ;
      RECT 2646.000 4.080 2647.200 4005.200 ;
      RECT 2656.880 4.080 2658.080 4005.200 ;
      RECT 2667.760 4.080 2668.960 4005.200 ;
      RECT 2678.640 4.080 2679.840 4005.200 ;
      RECT 2689.520 4.080 2690.720 4005.200 ;
      RECT 2700.400 4.080 2701.600 4005.200 ;
      RECT 2711.280 4.080 2712.480 4005.200 ;
      RECT 2722.160 4.080 2723.360 4005.200 ;
      RECT 2733.040 4.080 2734.240 4005.200 ;
      RECT 2743.920 4.080 2745.120 4005.200 ;
      RECT 2754.800 4.080 2756.000 4005.200 ;
      RECT 2765.680 4.080 2766.880 4005.200 ;
      RECT 2776.560 4.080 2777.760 4005.200 ;
      RECT 2787.440 4.080 2788.640 4005.200 ;
      RECT 2798.320 4.080 2799.520 4005.200 ;
      RECT 2809.200 4.080 2810.400 4005.200 ;
      RECT 2820.080 4.080 2821.280 4005.200 ;
      RECT 2830.960 4.080 2832.160 4005.200 ;
      RECT 2841.840 4.080 2843.040 4005.200 ;
      RECT 2852.720 4.080 2853.920 4005.200 ;
      RECT 2863.600 4.080 2864.800 4005.200 ;
      RECT 2874.480 4.080 2875.680 4005.200 ;
      RECT 2885.360 4.080 2886.560 4005.200 ;
      RECT 2896.240 4.080 2897.440 4005.200 ;
      RECT 2907.120 4.080 2908.320 4005.200 ;
      RECT 2918.000 4.080 2919.200 4005.200 ;
      RECT 2928.880 4.080 2930.080 4005.200 ;
      RECT 2939.760 4.080 2940.960 4005.200 ;
      RECT 2950.640 4.080 2951.840 4005.200 ;
      RECT 2961.520 4.080 2962.720 4005.200 ;
      RECT 2972.400 4.080 2973.600 4005.200 ;
      RECT 2983.280 4.080 2984.480 4005.200 ;
      RECT 2994.160 4.080 2995.360 4005.200 ;
      RECT 3005.040 4.080 3006.240 4005.200 ;
      RECT 3015.920 4.080 3017.120 4005.200 ;
      RECT 3026.800 4.080 3028.000 4005.200 ;
      RECT 3037.680 4.080 3038.880 4005.200 ;
      RECT 3048.560 4.080 3049.760 4005.200 ;
      RECT 3059.440 4.080 3060.640 4005.200 ;
      RECT 3070.320 4.080 3071.520 4005.200 ;
      RECT 3081.200 4.080 3082.400 4005.200 ;
      RECT 3092.080 4.080 3093.280 4005.200 ;
      RECT 3102.960 4.080 3104.160 4005.200 ;
      RECT 3113.840 4.080 3115.040 4005.200 ;
      RECT 3124.720 4.080 3125.920 4005.200 ;
      RECT 3135.600 4.080 3136.800 4005.200 ;
      RECT 3146.480 4.080 3147.680 4005.200 ;
      RECT 3157.360 4.080 3158.560 4005.200 ;
      RECT 3168.240 4.080 3169.440 4005.200 ;
      RECT 3179.120 4.080 3180.320 4005.200 ;
      RECT 3190.000 4.080 3191.200 4005.200 ;
      RECT 3200.880 4.080 3202.080 4005.200 ;
      RECT 3211.760 4.080 3212.960 4005.200 ;
      RECT 3222.640 4.080 3223.840 4005.200 ;
      RECT 3233.520 4.080 3234.720 4005.200 ;
      RECT 3244.400 4.080 3245.600 4005.200 ;
      RECT 3255.280 4.080 3256.480 4005.200 ;
      RECT 3266.160 4.080 3267.360 4005.200 ;
      RECT 3277.040 4.080 3278.240 4005.200 ;
      RECT 3287.920 4.080 3289.120 4005.200 ;
      RECT 3298.800 4.080 3300.000 4005.200 ;
      RECT 3309.680 4.080 3310.880 4005.200 ;
      RECT 3320.560 4.080 3321.760 4005.200 ;
      RECT 3331.440 4.080 3332.640 4005.200 ;
      RECT 3342.320 4.080 3343.520 4005.200 ;
      RECT 3353.200 4.080 3354.400 4005.200 ;
      RECT 3364.080 4.080 3365.280 4005.200 ;
      RECT 3374.960 4.080 3376.160 4005.200 ;
      RECT 3385.840 4.080 3387.040 4005.200 ;
      RECT 3396.720 4.080 3397.920 4005.200 ;
      RECT 3407.600 4.080 3408.800 4005.200 ;
      RECT 3418.480 4.080 3419.680 4005.200 ;
      RECT 3429.360 4.080 3430.560 4005.200 ;
      RECT 3440.240 4.080 3441.440 4005.200 ;
      RECT 3451.120 4.080 3452.320 4005.200 ;
      RECT 3462.000 4.080 3463.200 4005.200 ;
      RECT 3472.880 4.080 3474.080 4005.200 ;
      RECT 3483.760 4.080 3484.960 4005.200 ;
      RECT 3494.640 4.080 3495.840 4005.200 ;
      RECT 3505.520 4.080 3506.720 4005.200 ;
      RECT 3516.400 4.080 3517.600 4005.200 ;
      RECT 3527.280 4.080 3528.480 4005.200 ;
      RECT 3538.160 4.080 3539.360 4005.200 ;
      RECT 3549.040 4.080 3550.240 4005.200 ;
      RECT 3559.920 4.080 3561.120 4005.200 ;
      RECT 3570.800 4.080 3572.000 4005.200 ;
      RECT 3581.680 4.080 3582.880 4005.200 ;
      RECT 3592.560 4.080 3593.760 4005.200 ;
      RECT 3603.440 4.080 3604.640 4005.200 ;
      RECT 3614.320 4.080 3615.520 4005.200 ;
      RECT 3625.200 4.080 3626.400 4005.200 ;
      RECT 3636.080 4.080 3637.280 4005.200 ;
      RECT 3646.960 4.080 3648.160 4005.200 ;
      RECT 3657.840 4.080 3659.040 4005.200 ;
      RECT 3668.720 4.080 3669.920 4005.200 ;
      RECT 3679.600 4.080 3680.800 4005.200 ;
      RECT 3690.480 4.080 3691.680 4005.200 ;
      RECT 3701.360 4.080 3702.560 4005.200 ;
      RECT 3712.240 4.080 3713.440 4005.200 ;
      RECT 3723.120 4.080 3724.320 4005.200 ;
      RECT 3734.000 4.080 3735.200 4005.200 ;
      RECT 3744.880 4.080 3746.080 4005.200 ;
      RECT 3755.760 4.080 3756.960 4005.200 ;
      RECT 3766.640 4.080 3767.840 4005.200 ;
      RECT 3777.520 4.080 3778.720 4005.200 ;
      RECT 3788.400 4.080 3789.600 4005.200 ;
      RECT 3799.280 4.080 3800.480 4005.200 ;
      RECT 3810.160 4.080 3811.360 4005.200 ;
      RECT 3821.040 4.080 3822.240 4005.200 ;
      RECT 3831.920 4.080 3833.120 4005.200 ;
      RECT 3842.800 4.080 3844.000 4005.200 ;
      RECT 3853.680 4.080 3854.880 4005.200 ;
      RECT 3864.560 4.080 3865.760 4005.200 ;
      RECT 3875.440 4.080 3876.640 4005.200 ;
      RECT 3886.320 4.080 3887.520 4005.200 ;
      RECT 3897.200 4.080 3898.400 4005.200 ;
      RECT 3908.080 4.080 3909.280 4005.200 ;
      RECT 3918.960 4.080 3920.160 4005.200 ;
      RECT 3929.840 4.080 3931.040 4005.200 ;
      RECT 3940.720 4.080 3941.920 4005.200 ;
      RECT 3951.600 4.080 3952.800 4005.200 ;
      RECT 3962.480 4.080 3963.680 4005.200 ;
      RECT 3973.360 4.080 3974.560 4005.200 ;
      RECT 3984.240 4.080 3985.440 4005.200 ;
      RECT 3995.120 4.080 3996.320 4005.200 ;
      RECT 4006.000 4.080 4007.200 4005.200 ;
      RECT 4016.880 4.080 4018.080 4005.200 ;
      RECT 4027.760 4.080 4028.960 4005.200 ;
      RECT 4038.640 4.080 4039.840 4005.200 ;
      RECT 4049.520 4.080 4050.720 4005.200 ;
      RECT 4060.400 4.080 4061.600 4005.200 ;
      RECT 4071.280 4.080 4072.480 4005.200 ;
      RECT 4082.160 4.080 4083.360 4005.200 ;
      RECT 4093.040 4.080 4094.240 4005.200 ;
      RECT 4103.920 4.080 4105.120 4005.200 ;
      RECT 4114.800 4.080 4116.000 4005.200 ;
      RECT 4125.680 4.080 4126.880 4005.200 ;
      RECT 4136.560 4.080 4137.760 4005.200 ;
      RECT 4147.440 4.080 4148.640 4005.200 ;
      RECT 4158.320 4.080 4159.520 4005.200 ;
      RECT 4169.200 4.080 4170.400 4005.200 ;
      RECT 4180.080 4.080 4181.280 4005.200 ;
      RECT 4190.960 4.080 4192.160 4005.200 ;
      RECT 4201.840 4.080 4203.040 4005.200 ;
      RECT 4212.720 4.080 4213.920 4005.200 ;
      RECT 4223.600 4.080 4224.800 4005.200 ;
      RECT 4234.480 4.080 4235.680 4005.200 ;
      RECT 4245.360 4.080 4246.560 4005.200 ;
      RECT 4256.240 4.080 4257.440 4005.200 ;
      RECT 4267.120 4.080 4268.320 4005.200 ;
      RECT 4278.000 4.080 4279.200 4005.200 ;
      RECT 4288.880 4.080 4290.080 4005.200 ;
      RECT 4299.760 4.080 4300.960 4005.200 ;
      RECT 4310.640 4.080 4311.840 4005.200 ;
      RECT 4321.520 4.080 4322.720 4005.200 ;
      RECT 4332.400 4.080 4333.600 4005.200 ;
      RECT 4343.280 4.080 4344.480 4005.200 ;
      RECT 4354.160 4.080 4355.360 4005.200 ;
      RECT 4365.040 4.080 4366.240 4005.200 ;
      RECT 4375.920 4.080 4377.120 4005.200 ;
      RECT 4386.800 4.080 4388.000 4005.200 ;
      RECT 4397.680 4.080 4398.880 4005.200 ;
      RECT 4408.560 4.080 4409.760 4005.200 ;
      RECT 4419.440 4.080 4420.640 4005.200 ;
      RECT 4430.320 4.080 4431.520 4005.200 ;
      RECT 4441.200 4.080 4442.400 4005.200 ;
      RECT 4452.080 4.080 4453.280 4005.200 ;
      RECT 4462.960 4.080 4464.160 4005.200 ;
      RECT 4473.840 4.080 4475.040 4005.200 ;
      RECT 4484.720 4.080 4485.920 4005.200 ;
      RECT 4495.600 4.080 4496.800 4005.200 ;
      RECT 4506.480 4.080 4507.680 4005.200 ;
      RECT 4517.360 4.080 4518.560 4005.200 ;
      RECT 4528.240 4.080 4529.440 4005.200 ;
      RECT 4539.120 4.080 4540.320 4005.200 ;
      RECT 4550.000 4.080 4551.200 4005.200 ;
      RECT 4560.880 4.080 4562.080 4005.200 ;
      RECT 4571.760 4.080 4572.960 4005.200 ;
      RECT 4582.640 4.080 4583.840 4005.200 ;
      RECT 4593.520 4.080 4594.720 4005.200 ;
      RECT 4604.400 4.080 4605.600 4005.200 ;
      RECT 4615.280 4.080 4616.480 4005.200 ;
      RECT 4626.160 4.080 4627.360 4005.200 ;
      RECT 4637.040 4.080 4638.240 4005.200 ;
      RECT 4647.920 4.080 4649.120 4005.200 ;
      RECT 4658.800 4.080 4660.000 4005.200 ;
      RECT 4669.680 4.080 4670.880 4005.200 ;
      RECT 4680.560 4.080 4681.760 4005.200 ;
      RECT 4691.440 4.080 4692.640 4005.200 ;
      RECT 4702.320 4.080 4703.520 4005.200 ;
      RECT 4713.200 4.080 4714.400 4005.200 ;
      RECT 4724.080 4.080 4725.280 4005.200 ;
      RECT 4734.960 4.080 4736.160 4005.200 ;
      RECT 4745.840 4.080 4747.040 4005.200 ;
      RECT 4756.720 4.080 4757.920 4005.200 ;
      RECT 4767.600 4.080 4768.800 4005.200 ;
      RECT 4778.480 4.080 4779.680 4005.200 ;
      RECT 4789.360 4.080 4790.560 4005.200 ;
      RECT 4800.240 4.080 4801.440 4005.200 ;
      RECT 4811.120 4.080 4812.320 4005.200 ;
      RECT 4822.000 4.080 4823.200 4005.200 ;
      RECT 4832.880 4.080 4834.080 4005.200 ;
      RECT 4843.760 4.080 4844.960 4005.200 ;
      RECT 4854.640 4.080 4855.840 4005.200 ;
      RECT 4865.520 4.080 4866.720 4005.200 ;
      RECT 4876.400 4.080 4877.600 4005.200 ;
      RECT 4887.280 4.080 4888.480 4005.200 ;
      RECT 4898.160 4.080 4899.360 4005.200 ;
      RECT 4909.040 4.080 4910.240 4005.200 ;
      RECT 4919.920 4.080 4921.120 4005.200 ;
    END
  END VSS
  PIN VDD
    DIRECTION INOUT ;
    USE POWER ;
    PORT
      LAYER met4 ;
      RECT 2.160 4.080 3.360 4005.200 ;
      RECT 13.040 4.080 14.240 4005.200 ;
      RECT 23.920 4.080 25.120 4005.200 ;
      RECT 34.800 4.080 36.000 4005.200 ;
      RECT 45.680 4.080 46.880 4005.200 ;
      RECT 56.560 4.080 57.760 4005.200 ;
      RECT 67.440 4.080 68.640 4005.200 ;
      RECT 78.320 4.080 79.520 4005.200 ;
      RECT 89.200 4.080 90.400 4005.200 ;
      RECT 100.080 4.080 101.280 4005.200 ;
      RECT 110.960 4.080 112.160 4005.200 ;
      RECT 121.840 4.080 123.040 4005.200 ;
      RECT 132.720 4.080 133.920 4005.200 ;
      RECT 143.600 4.080 144.800 4005.200 ;
      RECT 154.480 4.080 155.680 4005.200 ;
      RECT 165.360 4.080 166.560 4005.200 ;
      RECT 176.240 4.080 177.440 4005.200 ;
      RECT 187.120 4.080 188.320 4005.200 ;
      RECT 198.000 4.080 199.200 4005.200 ;
      RECT 208.880 4.080 210.080 4005.200 ;
      RECT 219.760 4.080 220.960 4005.200 ;
      RECT 230.640 4.080 231.840 4005.200 ;
      RECT 241.520 4.080 242.720 4005.200 ;
      RECT 252.400 4.080 253.600 4005.200 ;
      RECT 263.280 4.080 264.480 4005.200 ;
      RECT 274.160 4.080 275.360 4005.200 ;
      RECT 285.040 4.080 286.240 4005.200 ;
      RECT 295.920 4.080 297.120 4005.200 ;
      RECT 306.800 4.080 308.000 4005.200 ;
      RECT 317.680 4.080 318.880 4005.200 ;
      RECT 328.560 4.080 329.760 4005.200 ;
      RECT 339.440 4.080 340.640 4005.200 ;
      RECT 350.320 4.080 351.520 4005.200 ;
      RECT 361.200 4.080 362.400 4005.200 ;
      RECT 372.080 4.080 373.280 4005.200 ;
      RECT 382.960 4.080 384.160 4005.200 ;
      RECT 393.840 4.080 395.040 4005.200 ;
      RECT 404.720 4.080 405.920 4005.200 ;
      RECT 415.600 4.080 416.800 4005.200 ;
      RECT 426.480 4.080 427.680 4005.200 ;
      RECT 437.360 4.080 438.560 4005.200 ;
      RECT 448.240 4.080 449.440 4005.200 ;
      RECT 459.120 4.080 460.320 4005.200 ;
      RECT 470.000 4.080 471.200 4005.200 ;
      RECT 480.880 4.080 482.080 4005.200 ;
      RECT 491.760 4.080 492.960 4005.200 ;
      RECT 502.640 4.080 503.840 4005.200 ;
      RECT 513.520 4.080 514.720 4005.200 ;
      RECT 524.400 4.080 525.600 4005.200 ;
      RECT 535.280 4.080 536.480 4005.200 ;
      RECT 546.160 4.080 547.360 4005.200 ;
      RECT 557.040 4.080 558.240 4005.200 ;
      RECT 567.920 4.080 569.120 4005.200 ;
      RECT 578.800 4.080 580.000 4005.200 ;
      RECT 589.680 4.080 590.880 4005.200 ;
      RECT 600.560 4.080 601.760 4005.200 ;
      RECT 611.440 4.080 612.640 4005.200 ;
      RECT 622.320 4.080 623.520 4005.200 ;
      RECT 633.200 4.080 634.400 4005.200 ;
      RECT 644.080 4.080 645.280 4005.200 ;
      RECT 654.960 4.080 656.160 4005.200 ;
      RECT 665.840 4.080 667.040 4005.200 ;
      RECT 676.720 4.080 677.920 4005.200 ;
      RECT 687.600 4.080 688.800 4005.200 ;
      RECT 698.480 4.080 699.680 4005.200 ;
      RECT 709.360 4.080 710.560 4005.200 ;
      RECT 720.240 4.080 721.440 4005.200 ;
      RECT 731.120 4.080 732.320 4005.200 ;
      RECT 742.000 4.080 743.200 4005.200 ;
      RECT 752.880 4.080 754.080 4005.200 ;
      RECT 763.760 4.080 764.960 4005.200 ;
      RECT 774.640 4.080 775.840 4005.200 ;
      RECT 785.520 4.080 786.720 4005.200 ;
      RECT 796.400 4.080 797.600 4005.200 ;
      RECT 807.280 4.080 808.480 4005.200 ;
      RECT 818.160 4.080 819.360 4005.200 ;
      RECT 829.040 4.080 830.240 4005.200 ;
      RECT 839.920 4.080 841.120 4005.200 ;
      RECT 850.800 4.080 852.000 4005.200 ;
      RECT 861.680 4.080 862.880 4005.200 ;
      RECT 872.560 4.080 873.760 4005.200 ;
      RECT 883.440 4.080 884.640 4005.200 ;
      RECT 894.320 4.080 895.520 4005.200 ;
      RECT 905.200 4.080 906.400 4005.200 ;
      RECT 916.080 4.080 917.280 4005.200 ;
      RECT 926.960 4.080 928.160 4005.200 ;
      RECT 937.840 4.080 939.040 4005.200 ;
      RECT 948.720 4.080 949.920 4005.200 ;
      RECT 959.600 4.080 960.800 4005.200 ;
      RECT 970.480 4.080 971.680 4005.200 ;
      RECT 981.360 4.080 982.560 4005.200 ;
      RECT 992.240 4.080 993.440 4005.200 ;
      RECT 1003.120 4.080 1004.320 4005.200 ;
      RECT 1014.000 4.080 1015.200 4005.200 ;
      RECT 1024.880 4.080 1026.080 4005.200 ;
      RECT 1035.760 4.080 1036.960 4005.200 ;
      RECT 1046.640 4.080 1047.840 4005.200 ;
      RECT 1057.520 4.080 1058.720 4005.200 ;
      RECT 1068.400 4.080 1069.600 4005.200 ;
      RECT 1079.280 4.080 1080.480 4005.200 ;
      RECT 1090.160 4.080 1091.360 4005.200 ;
      RECT 1101.040 4.080 1102.240 4005.200 ;
      RECT 1111.920 4.080 1113.120 4005.200 ;
      RECT 1122.800 4.080 1124.000 4005.200 ;
      RECT 1133.680 4.080 1134.880 4005.200 ;
      RECT 1144.560 4.080 1145.760 4005.200 ;
      RECT 1155.440 4.080 1156.640 4005.200 ;
      RECT 1166.320 4.080 1167.520 4005.200 ;
      RECT 1177.200 4.080 1178.400 4005.200 ;
      RECT 1188.080 4.080 1189.280 4005.200 ;
      RECT 1198.960 4.080 1200.160 4005.200 ;
      RECT 1209.840 4.080 1211.040 4005.200 ;
      RECT 1220.720 4.080 1221.920 4005.200 ;
      RECT 1231.600 4.080 1232.800 4005.200 ;
      RECT 1242.480 4.080 1243.680 4005.200 ;
      RECT 1253.360 4.080 1254.560 4005.200 ;
      RECT 1264.240 4.080 1265.440 4005.200 ;
      RECT 1275.120 4.080 1276.320 4005.200 ;
      RECT 1286.000 4.080 1287.200 4005.200 ;
      RECT 1296.880 4.080 1298.080 4005.200 ;
      RECT 1307.760 4.080 1308.960 4005.200 ;
      RECT 1318.640 4.080 1319.840 4005.200 ;
      RECT 1329.520 4.080 1330.720 4005.200 ;
      RECT 1340.400 4.080 1341.600 4005.200 ;
      RECT 1351.280 4.080 1352.480 4005.200 ;
      RECT 1362.160 4.080 1363.360 4005.200 ;
      RECT 1373.040 4.080 1374.240 4005.200 ;
      RECT 1383.920 4.080 1385.120 4005.200 ;
      RECT 1394.800 4.080 1396.000 4005.200 ;
      RECT 1405.680 4.080 1406.880 4005.200 ;
      RECT 1416.560 4.080 1417.760 4005.200 ;
      RECT 1427.440 4.080 1428.640 4005.200 ;
      RECT 1438.320 4.080 1439.520 4005.200 ;
      RECT 1449.200 4.080 1450.400 4005.200 ;
      RECT 1460.080 4.080 1461.280 4005.200 ;
      RECT 1470.960 4.080 1472.160 4005.200 ;
      RECT 1481.840 4.080 1483.040 4005.200 ;
      RECT 1492.720 4.080 1493.920 4005.200 ;
      RECT 1503.600 4.080 1504.800 4005.200 ;
      RECT 1514.480 4.080 1515.680 4005.200 ;
      RECT 1525.360 4.080 1526.560 4005.200 ;
      RECT 1536.240 4.080 1537.440 4005.200 ;
      RECT 1547.120 4.080 1548.320 4005.200 ;
      RECT 1558.000 4.080 1559.200 4005.200 ;
      RECT 1568.880 4.080 1570.080 4005.200 ;
      RECT 1579.760 4.080 1580.960 4005.200 ;
      RECT 1590.640 4.080 1591.840 4005.200 ;
      RECT 1601.520 4.080 1602.720 4005.200 ;
      RECT 1612.400 4.080 1613.600 4005.200 ;
      RECT 1623.280 4.080 1624.480 4005.200 ;
      RECT 1634.160 4.080 1635.360 4005.200 ;
      RECT 1645.040 4.080 1646.240 4005.200 ;
      RECT 1655.920 4.080 1657.120 4005.200 ;
      RECT 1666.800 4.080 1668.000 4005.200 ;
      RECT 1677.680 4.080 1678.880 4005.200 ;
      RECT 1688.560 4.080 1689.760 4005.200 ;
      RECT 1699.440 4.080 1700.640 4005.200 ;
      RECT 1710.320 4.080 1711.520 4005.200 ;
      RECT 1721.200 4.080 1722.400 4005.200 ;
      RECT 1732.080 4.080 1733.280 4005.200 ;
      RECT 1742.960 4.080 1744.160 4005.200 ;
      RECT 1753.840 4.080 1755.040 4005.200 ;
      RECT 1764.720 4.080 1765.920 4005.200 ;
      RECT 1775.600 4.080 1776.800 4005.200 ;
      RECT 1786.480 4.080 1787.680 4005.200 ;
      RECT 1797.360 4.080 1798.560 4005.200 ;
      RECT 1808.240 4.080 1809.440 4005.200 ;
      RECT 1819.120 4.080 1820.320 4005.200 ;
      RECT 1830.000 4.080 1831.200 4005.200 ;
      RECT 1840.880 4.080 1842.080 4005.200 ;
      RECT 1851.760 4.080 1852.960 4005.200 ;
      RECT 1862.640 4.080 1863.840 4005.200 ;
      RECT 1873.520 4.080 1874.720 4005.200 ;
      RECT 1884.400 4.080 1885.600 4005.200 ;
      RECT 1895.280 4.080 1896.480 4005.200 ;
      RECT 1906.160 4.080 1907.360 4005.200 ;
      RECT 1917.040 4.080 1918.240 4005.200 ;
      RECT 1927.920 4.080 1929.120 4005.200 ;
      RECT 1938.800 4.080 1940.000 4005.200 ;
      RECT 1949.680 4.080 1950.880 4005.200 ;
      RECT 1960.560 4.080 1961.760 4005.200 ;
      RECT 1971.440 4.080 1972.640 4005.200 ;
      RECT 1982.320 4.080 1983.520 4005.200 ;
      RECT 1993.200 4.080 1994.400 4005.200 ;
      RECT 2004.080 4.080 2005.280 4005.200 ;
      RECT 2014.960 4.080 2016.160 4005.200 ;
      RECT 2025.840 4.080 2027.040 4005.200 ;
      RECT 2036.720 4.080 2037.920 4005.200 ;
      RECT 2047.600 4.080 2048.800 4005.200 ;
      RECT 2058.480 4.080 2059.680 4005.200 ;
      RECT 2069.360 4.080 2070.560 4005.200 ;
      RECT 2080.240 4.080 2081.440 4005.200 ;
      RECT 2091.120 4.080 2092.320 4005.200 ;
      RECT 2102.000 4.080 2103.200 4005.200 ;
      RECT 2112.880 4.080 2114.080 4005.200 ;
      RECT 2123.760 4.080 2124.960 4005.200 ;
      RECT 2134.640 4.080 2135.840 4005.200 ;
      RECT 2145.520 4.080 2146.720 4005.200 ;
      RECT 2156.400 4.080 2157.600 4005.200 ;
      RECT 2167.280 4.080 2168.480 4005.200 ;
      RECT 2178.160 4.080 2179.360 4005.200 ;
      RECT 2189.040 4.080 2190.240 4005.200 ;
      RECT 2199.920 4.080 2201.120 4005.200 ;
      RECT 2210.800 4.080 2212.000 4005.200 ;
      RECT 2221.680 4.080 2222.880 4005.200 ;
      RECT 2232.560 4.080 2233.760 4005.200 ;
      RECT 2243.440 4.080 2244.640 4005.200 ;
      RECT 2254.320 4.080 2255.520 4005.200 ;
      RECT 2265.200 4.080 2266.400 4005.200 ;
      RECT 2276.080 4.080 2277.280 4005.200 ;
      RECT 2286.960 4.080 2288.160 4005.200 ;
      RECT 2297.840 4.080 2299.040 4005.200 ;
      RECT 2308.720 4.080 2309.920 4005.200 ;
      RECT 2319.600 4.080 2320.800 4005.200 ;
      RECT 2330.480 4.080 2331.680 4005.200 ;
      RECT 2341.360 4.080 2342.560 4005.200 ;
      RECT 2352.240 4.080 2353.440 4005.200 ;
      RECT 2363.120 4.080 2364.320 4005.200 ;
      RECT 2374.000 4.080 2375.200 4005.200 ;
      RECT 2384.880 4.080 2386.080 4005.200 ;
      RECT 2395.760 4.080 2396.960 4005.200 ;
      RECT 2406.640 4.080 2407.840 4005.200 ;
      RECT 2417.520 4.080 2418.720 4005.200 ;
      RECT 2428.400 4.080 2429.600 4005.200 ;
      RECT 2439.280 4.080 2440.480 4005.200 ;
      RECT 2450.160 4.080 2451.360 4005.200 ;
      RECT 2461.040 4.080 2462.240 4005.200 ;
      RECT 2471.920 4.080 2473.120 4005.200 ;
      RECT 2482.800 4.080 2484.000 4005.200 ;
      RECT 2493.680 4.080 2494.880 4005.200 ;
      RECT 2504.560 4.080 2505.760 4005.200 ;
      RECT 2515.440 4.080 2516.640 4005.200 ;
      RECT 2526.320 4.080 2527.520 4005.200 ;
      RECT 2537.200 4.080 2538.400 4005.200 ;
      RECT 2548.080 4.080 2549.280 4005.200 ;
      RECT 2558.960 4.080 2560.160 4005.200 ;
      RECT 2569.840 4.080 2571.040 4005.200 ;
      RECT 2580.720 4.080 2581.920 4005.200 ;
      RECT 2591.600 4.080 2592.800 4005.200 ;
      RECT 2602.480 4.080 2603.680 4005.200 ;
      RECT 2613.360 4.080 2614.560 4005.200 ;
      RECT 2624.240 4.080 2625.440 4005.200 ;
      RECT 2635.120 4.080 2636.320 4005.200 ;
      RECT 2646.000 4.080 2647.200 4005.200 ;
      RECT 2656.880 4.080 2658.080 4005.200 ;
      RECT 2667.760 4.080 2668.960 4005.200 ;
      RECT 2678.640 4.080 2679.840 4005.200 ;
      RECT 2689.520 4.080 2690.720 4005.200 ;
      RECT 2700.400 4.080 2701.600 4005.200 ;
      RECT 2711.280 4.080 2712.480 4005.200 ;
      RECT 2722.160 4.080 2723.360 4005.200 ;
      RECT 2733.040 4.080 2734.240 4005.200 ;
      RECT 2743.920 4.080 2745.120 4005.200 ;
      RECT 2754.800 4.080 2756.000 4005.200 ;
      RECT 2765.680 4.080 2766.880 4005.200 ;
      RECT 2776.560 4.080 2777.760 4005.200 ;
      RECT 2787.440 4.080 2788.640 4005.200 ;
      RECT 2798.320 4.080 2799.520 4005.200 ;
      RECT 2809.200 4.080 2810.400 4005.200 ;
      RECT 2820.080 4.080 2821.280 4005.200 ;
      RECT 2830.960 4.080 2832.160 4005.200 ;
      RECT 2841.840 4.080 2843.040 4005.200 ;
      RECT 2852.720 4.080 2853.920 4005.200 ;
      RECT 2863.600 4.080 2864.800 4005.200 ;
      RECT 2874.480 4.080 2875.680 4005.200 ;
      RECT 2885.360 4.080 2886.560 4005.200 ;
      RECT 2896.240 4.080 2897.440 4005.200 ;
      RECT 2907.120 4.080 2908.320 4005.200 ;
      RECT 2918.000 4.080 2919.200 4005.200 ;
      RECT 2928.880 4.080 2930.080 4005.200 ;
      RECT 2939.760 4.080 2940.960 4005.200 ;
      RECT 2950.640 4.080 2951.840 4005.200 ;
      RECT 2961.520 4.080 2962.720 4005.200 ;
      RECT 2972.400 4.080 2973.600 4005.200 ;
      RECT 2983.280 4.080 2984.480 4005.200 ;
      RECT 2994.160 4.080 2995.360 4005.200 ;
      RECT 3005.040 4.080 3006.240 4005.200 ;
      RECT 3015.920 4.080 3017.120 4005.200 ;
      RECT 3026.800 4.080 3028.000 4005.200 ;
      RECT 3037.680 4.080 3038.880 4005.200 ;
      RECT 3048.560 4.080 3049.760 4005.200 ;
      RECT 3059.440 4.080 3060.640 4005.200 ;
      RECT 3070.320 4.080 3071.520 4005.200 ;
      RECT 3081.200 4.080 3082.400 4005.200 ;
      RECT 3092.080 4.080 3093.280 4005.200 ;
      RECT 3102.960 4.080 3104.160 4005.200 ;
      RECT 3113.840 4.080 3115.040 4005.200 ;
      RECT 3124.720 4.080 3125.920 4005.200 ;
      RECT 3135.600 4.080 3136.800 4005.200 ;
      RECT 3146.480 4.080 3147.680 4005.200 ;
      RECT 3157.360 4.080 3158.560 4005.200 ;
      RECT 3168.240 4.080 3169.440 4005.200 ;
      RECT 3179.120 4.080 3180.320 4005.200 ;
      RECT 3190.000 4.080 3191.200 4005.200 ;
      RECT 3200.880 4.080 3202.080 4005.200 ;
      RECT 3211.760 4.080 3212.960 4005.200 ;
      RECT 3222.640 4.080 3223.840 4005.200 ;
      RECT 3233.520 4.080 3234.720 4005.200 ;
      RECT 3244.400 4.080 3245.600 4005.200 ;
      RECT 3255.280 4.080 3256.480 4005.200 ;
      RECT 3266.160 4.080 3267.360 4005.200 ;
      RECT 3277.040 4.080 3278.240 4005.200 ;
      RECT 3287.920 4.080 3289.120 4005.200 ;
      RECT 3298.800 4.080 3300.000 4005.200 ;
      RECT 3309.680 4.080 3310.880 4005.200 ;
      RECT 3320.560 4.080 3321.760 4005.200 ;
      RECT 3331.440 4.080 3332.640 4005.200 ;
      RECT 3342.320 4.080 3343.520 4005.200 ;
      RECT 3353.200 4.080 3354.400 4005.200 ;
      RECT 3364.080 4.080 3365.280 4005.200 ;
      RECT 3374.960 4.080 3376.160 4005.200 ;
      RECT 3385.840 4.080 3387.040 4005.200 ;
      RECT 3396.720 4.080 3397.920 4005.200 ;
      RECT 3407.600 4.080 3408.800 4005.200 ;
      RECT 3418.480 4.080 3419.680 4005.200 ;
      RECT 3429.360 4.080 3430.560 4005.200 ;
      RECT 3440.240 4.080 3441.440 4005.200 ;
      RECT 3451.120 4.080 3452.320 4005.200 ;
      RECT 3462.000 4.080 3463.200 4005.200 ;
      RECT 3472.880 4.080 3474.080 4005.200 ;
      RECT 3483.760 4.080 3484.960 4005.200 ;
      RECT 3494.640 4.080 3495.840 4005.200 ;
      RECT 3505.520 4.080 3506.720 4005.200 ;
      RECT 3516.400 4.080 3517.600 4005.200 ;
      RECT 3527.280 4.080 3528.480 4005.200 ;
      RECT 3538.160 4.080 3539.360 4005.200 ;
      RECT 3549.040 4.080 3550.240 4005.200 ;
      RECT 3559.920 4.080 3561.120 4005.200 ;
      RECT 3570.800 4.080 3572.000 4005.200 ;
      RECT 3581.680 4.080 3582.880 4005.200 ;
      RECT 3592.560 4.080 3593.760 4005.200 ;
      RECT 3603.440 4.080 3604.640 4005.200 ;
      RECT 3614.320 4.080 3615.520 4005.200 ;
      RECT 3625.200 4.080 3626.400 4005.200 ;
      RECT 3636.080 4.080 3637.280 4005.200 ;
      RECT 3646.960 4.080 3648.160 4005.200 ;
      RECT 3657.840 4.080 3659.040 4005.200 ;
      RECT 3668.720 4.080 3669.920 4005.200 ;
      RECT 3679.600 4.080 3680.800 4005.200 ;
      RECT 3690.480 4.080 3691.680 4005.200 ;
      RECT 3701.360 4.080 3702.560 4005.200 ;
      RECT 3712.240 4.080 3713.440 4005.200 ;
      RECT 3723.120 4.080 3724.320 4005.200 ;
      RECT 3734.000 4.080 3735.200 4005.200 ;
      RECT 3744.880 4.080 3746.080 4005.200 ;
      RECT 3755.760 4.080 3756.960 4005.200 ;
      RECT 3766.640 4.080 3767.840 4005.200 ;
      RECT 3777.520 4.080 3778.720 4005.200 ;
      RECT 3788.400 4.080 3789.600 4005.200 ;
      RECT 3799.280 4.080 3800.480 4005.200 ;
      RECT 3810.160 4.080 3811.360 4005.200 ;
      RECT 3821.040 4.080 3822.240 4005.200 ;
      RECT 3831.920 4.080 3833.120 4005.200 ;
      RECT 3842.800 4.080 3844.000 4005.200 ;
      RECT 3853.680 4.080 3854.880 4005.200 ;
      RECT 3864.560 4.080 3865.760 4005.200 ;
      RECT 3875.440 4.080 3876.640 4005.200 ;
      RECT 3886.320 4.080 3887.520 4005.200 ;
      RECT 3897.200 4.080 3898.400 4005.200 ;
      RECT 3908.080 4.080 3909.280 4005.200 ;
      RECT 3918.960 4.080 3920.160 4005.200 ;
      RECT 3929.840 4.080 3931.040 4005.200 ;
      RECT 3940.720 4.080 3941.920 4005.200 ;
      RECT 3951.600 4.080 3952.800 4005.200 ;
      RECT 3962.480 4.080 3963.680 4005.200 ;
      RECT 3973.360 4.080 3974.560 4005.200 ;
      RECT 3984.240 4.080 3985.440 4005.200 ;
      RECT 3995.120 4.080 3996.320 4005.200 ;
      RECT 4006.000 4.080 4007.200 4005.200 ;
      RECT 4016.880 4.080 4018.080 4005.200 ;
      RECT 4027.760 4.080 4028.960 4005.200 ;
      RECT 4038.640 4.080 4039.840 4005.200 ;
      RECT 4049.520 4.080 4050.720 4005.200 ;
      RECT 4060.400 4.080 4061.600 4005.200 ;
      RECT 4071.280 4.080 4072.480 4005.200 ;
      RECT 4082.160 4.080 4083.360 4005.200 ;
      RECT 4093.040 4.080 4094.240 4005.200 ;
      RECT 4103.920 4.080 4105.120 4005.200 ;
      RECT 4114.800 4.080 4116.000 4005.200 ;
      RECT 4125.680 4.080 4126.880 4005.200 ;
      RECT 4136.560 4.080 4137.760 4005.200 ;
      RECT 4147.440 4.080 4148.640 4005.200 ;
      RECT 4158.320 4.080 4159.520 4005.200 ;
      RECT 4169.200 4.080 4170.400 4005.200 ;
      RECT 4180.080 4.080 4181.280 4005.200 ;
      RECT 4190.960 4.080 4192.160 4005.200 ;
      RECT 4201.840 4.080 4203.040 4005.200 ;
      RECT 4212.720 4.080 4213.920 4005.200 ;
      RECT 4223.600 4.080 4224.800 4005.200 ;
      RECT 4234.480 4.080 4235.680 4005.200 ;
      RECT 4245.360 4.080 4246.560 4005.200 ;
      RECT 4256.240 4.080 4257.440 4005.200 ;
      RECT 4267.120 4.080 4268.320 4005.200 ;
      RECT 4278.000 4.080 4279.200 4005.200 ;
      RECT 4288.880 4.080 4290.080 4005.200 ;
      RECT 4299.760 4.080 4300.960 4005.200 ;
      RECT 4310.640 4.080 4311.840 4005.200 ;
      RECT 4321.520 4.080 4322.720 4005.200 ;
      RECT 4332.400 4.080 4333.600 4005.200 ;
      RECT 4343.280 4.080 4344.480 4005.200 ;
      RECT 4354.160 4.080 4355.360 4005.200 ;
      RECT 4365.040 4.080 4366.240 4005.200 ;
      RECT 4375.920 4.080 4377.120 4005.200 ;
      RECT 4386.800 4.080 4388.000 4005.200 ;
      RECT 4397.680 4.080 4398.880 4005.200 ;
      RECT 4408.560 4.080 4409.760 4005.200 ;
      RECT 4419.440 4.080 4420.640 4005.200 ;
      RECT 4430.320 4.080 4431.520 4005.200 ;
      RECT 4441.200 4.080 4442.400 4005.200 ;
      RECT 4452.080 4.080 4453.280 4005.200 ;
      RECT 4462.960 4.080 4464.160 4005.200 ;
      RECT 4473.840 4.080 4475.040 4005.200 ;
      RECT 4484.720 4.080 4485.920 4005.200 ;
      RECT 4495.600 4.080 4496.800 4005.200 ;
      RECT 4506.480 4.080 4507.680 4005.200 ;
      RECT 4517.360 4.080 4518.560 4005.200 ;
      RECT 4528.240 4.080 4529.440 4005.200 ;
      RECT 4539.120 4.080 4540.320 4005.200 ;
      RECT 4550.000 4.080 4551.200 4005.200 ;
      RECT 4560.880 4.080 4562.080 4005.200 ;
      RECT 4571.760 4.080 4572.960 4005.200 ;
      RECT 4582.640 4.080 4583.840 4005.200 ;
      RECT 4593.520 4.080 4594.720 4005.200 ;
      RECT 4604.400 4.080 4605.600 4005.200 ;
      RECT 4615.280 4.080 4616.480 4005.200 ;
      RECT 4626.160 4.080 4627.360 4005.200 ;
      RECT 4637.040 4.080 4638.240 4005.200 ;
      RECT 4647.920 4.080 4649.120 4005.200 ;
      RECT 4658.800 4.080 4660.000 4005.200 ;
      RECT 4669.680 4.080 4670.880 4005.200 ;
      RECT 4680.560 4.080 4681.760 4005.200 ;
      RECT 4691.440 4.080 4692.640 4005.200 ;
      RECT 4702.320 4.080 4703.520 4005.200 ;
      RECT 4713.200 4.080 4714.400 4005.200 ;
      RECT 4724.080 4.080 4725.280 4005.200 ;
      RECT 4734.960 4.080 4736.160 4005.200 ;
      RECT 4745.840 4.080 4747.040 4005.200 ;
      RECT 4756.720 4.080 4757.920 4005.200 ;
      RECT 4767.600 4.080 4768.800 4005.200 ;
      RECT 4778.480 4.080 4779.680 4005.200 ;
      RECT 4789.360 4.080 4790.560 4005.200 ;
      RECT 4800.240 4.080 4801.440 4005.200 ;
      RECT 4811.120 4.080 4812.320 4005.200 ;
      RECT 4822.000 4.080 4823.200 4005.200 ;
      RECT 4832.880 4.080 4834.080 4005.200 ;
      RECT 4843.760 4.080 4844.960 4005.200 ;
      RECT 4854.640 4.080 4855.840 4005.200 ;
      RECT 4865.520 4.080 4866.720 4005.200 ;
      RECT 4876.400 4.080 4877.600 4005.200 ;
      RECT 4887.280 4.080 4888.480 4005.200 ;
      RECT 4898.160 4.080 4899.360 4005.200 ;
      RECT 4909.040 4.080 4910.240 4005.200 ;
      RECT 4919.920 4.080 4921.120 4005.200 ;
    END
  END VDD
  OBS
    LAYER met1 ;
    RECT 0 0 4930.740 4009.280 ;
    LAYER met2 ;
    RECT 0 0 4930.740 4009.280 ;
    LAYER met3 ;
    RECT 0 0 4930.740 4009.280 ;
    LAYER met4 ;
    RECT 0 0 4930.740 4009.280 ;
  END
END fakeram_w16_l32768

END LIBRARY
